VERSION 5.7 ;
  NOWIREEXTENSIONATPIN ON ;
  DIVIDERCHAR "/" ;
  BUSBITCHARS "[]" ;
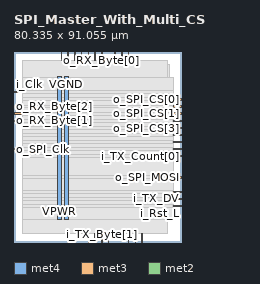
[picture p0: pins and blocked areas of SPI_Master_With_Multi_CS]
MACRO SPI_Master_With_Multi_CS
  CLASS BLOCK ;
  FOREIGN SPI_Master_With_Multi_CS ;
  ORIGIN 0.000 0.000 ;
  SIZE 80.335 BY 91.055 ;
  PIN VGND
    DIRECTION INOUT ;
    USE GROUND ;
    PORT
      LAYER met4 ;
        RECT 24.340 10.640 25.940 79.120 ;
    END
  END VGND
  PIN VPWR
    DIRECTION INOUT ;
    USE POWER ;
    PORT
      LAYER met4 ;
        RECT 21.040 10.640 22.640 79.120 ;
    END
  END VPWR
  PIN i_Clk
    DIRECTION INPUT ;
    USE SIGNAL ;
    ANTENNAGATEAREA 0.852000 ;
    PORT
      LAYER met3 ;
        RECT 0.000 71.440 4.000 72.040 ;
    END
  END i_Clk
  PIN i_Rst_L
    DIRECTION INPUT ;
    USE SIGNAL ;
    ANTENNAGATEAREA 0.196500 ;
    PORT
      LAYER met3 ;
        RECT 76.335 17.040 80.335 17.640 ;
    END
  END i_Rst_L
  PIN i_SPI_MISO
    DIRECTION INPUT ;
    USE SIGNAL ;
    ANTENNAGATEAREA 0.213000 ;
    PORT
      LAYER met2 ;
        RECT 29.070 87.055 29.350 91.055 ;
    END
  END i_SPI_MISO
  PIN i_Slave_Select[0]
    DIRECTION INPUT ;
    USE SIGNAL ;
    ANTENNAGATEAREA 0.196500 ;
    PORT
      LAYER met3 ;
        RECT 76.335 51.040 80.335 51.640 ;
    END
  END i_Slave_Select[0]
  PIN i_Slave_Select[1]
    DIRECTION INPUT ;
    USE SIGNAL ;
    ANTENNAGATEAREA 0.196500 ;
    PORT
      LAYER met3 ;
        RECT 76.335 54.440 80.335 55.040 ;
    END
  END i_Slave_Select[1]
  PIN i_TX_Byte[0]
    DIRECTION INPUT ;
    USE SIGNAL ;
    ANTENNAGATEAREA 0.196500 ;
    PORT
      LAYER met2 ;
        RECT 45.170 0.000 45.450 4.000 ;
    END
  END i_TX_Byte[0]
  PIN i_TX_Byte[1]
    DIRECTION INPUT ;
    USE SIGNAL ;
    ANTENNAGATEAREA 0.196500 ;
    PORT
      LAYER met2 ;
        RECT 41.950 0.000 42.230 4.000 ;
    END
  END i_TX_Byte[1]
  PIN i_TX_Byte[2]
    DIRECTION INPUT ;
    USE SIGNAL ;
    ANTENNAGATEAREA 0.196500 ;
    PORT
      LAYER met2 ;
        RECT 35.510 0.000 35.790 4.000 ;
    END
  END i_TX_Byte[2]
  PIN i_TX_Byte[3]
    DIRECTION INPUT ;
    USE SIGNAL ;
    ANTENNAGATEAREA 0.196500 ;
    PORT
      LAYER met2 ;
        RECT 38.730 0.000 39.010 4.000 ;
    END
  END i_TX_Byte[3]
  PIN i_TX_Byte[4]
    DIRECTION INPUT ;
    USE SIGNAL ;
    ANTENNAGATEAREA 0.196500 ;
    PORT
      LAYER met3 ;
        RECT 76.335 23.840 80.335 24.440 ;
    END
  END i_TX_Byte[4]
  PIN i_TX_Byte[5]
    DIRECTION INPUT ;
    USE SIGNAL ;
    ANTENNAGATEAREA 0.196500 ;
    PORT
      LAYER met2 ;
        RECT 61.270 0.000 61.550 4.000 ;
    END
  END i_TX_Byte[5]
  PIN i_TX_Byte[6]
    DIRECTION INPUT ;
    USE SIGNAL ;
    ANTENNAGATEAREA 0.196500 ;
    PORT
      LAYER met2 ;
        RECT 54.830 0.000 55.110 4.000 ;
    END
  END i_TX_Byte[6]
  PIN i_TX_Byte[7]
    DIRECTION INPUT ;
    USE SIGNAL ;
    ANTENNAGATEAREA 0.196500 ;
    PORT
      LAYER met2 ;
        RECT 58.050 0.000 58.330 4.000 ;
    END
  END i_TX_Byte[7]
  PIN i_TX_Count[0]
    DIRECTION INPUT ;
    USE SIGNAL ;
    ANTENNAGATEAREA 0.196500 ;
    PORT
      LAYER met3 ;
        RECT 76.335 40.840 80.335 41.440 ;
    END
  END i_TX_Count[0]
  PIN i_TX_Count[1]
    DIRECTION INPUT ;
    USE SIGNAL ;
    ANTENNAGATEAREA 0.196500 ;
    PORT
      LAYER met3 ;
        RECT 76.335 44.240 80.335 44.840 ;
    END
  END i_TX_Count[1]
  PIN i_TX_DV
    DIRECTION INPUT ;
    USE SIGNAL ;
    ANTENNAGATEAREA 0.196500 ;
    PORT
      LAYER met3 ;
        RECT 76.335 20.440 80.335 21.040 ;
    END
  END i_TX_DV
  PIN o_RX_Byte[0]
    DIRECTION OUTPUT ;
    USE SIGNAL ;
    ANTENNADIFFAREA 0.445500 ;
    PORT
      LAYER met2 ;
        RECT 41.950 87.055 42.230 91.055 ;
    END
  END o_RX_Byte[0]
  PIN o_RX_Byte[1]
    DIRECTION OUTPUT ;
    USE SIGNAL ;
    ANTENNADIFFAREA 0.445500 ;
    PORT
      LAYER met3 ;
        RECT 0.000 57.840 4.000 58.440 ;
    END
  END o_RX_Byte[1]
  PIN o_RX_Byte[2]
    DIRECTION OUTPUT ;
    USE SIGNAL ;
    ANTENNADIFFAREA 0.445500 ;
    PORT
      LAYER met3 ;
        RECT 0.000 61.240 4.000 61.840 ;
    END
  END o_RX_Byte[2]
  PIN o_RX_Byte[3]
    DIRECTION OUTPUT ;
    USE SIGNAL ;
    ANTENNADIFFAREA 0.445500 ;
    PORT
      LAYER met2 ;
        RECT 38.730 87.055 39.010 91.055 ;
    END
  END o_RX_Byte[3]
  PIN o_RX_Byte[4]
    DIRECTION OUTPUT ;
    USE SIGNAL ;
    ANTENNADIFFAREA 0.445500 ;
    PORT
      LAYER met2 ;
        RECT 32.290 87.055 32.570 91.055 ;
    END
  END o_RX_Byte[4]
  PIN o_RX_Byte[5]
    DIRECTION OUTPUT ;
    USE SIGNAL ;
    ANTENNADIFFAREA 0.445500 ;
    PORT
      LAYER met2 ;
        RECT 25.850 87.055 26.130 91.055 ;
    END
  END o_RX_Byte[5]
  PIN o_RX_Byte[6]
    DIRECTION OUTPUT ;
    USE SIGNAL ;
    ANTENNADIFFAREA 0.445500 ;
    PORT
      LAYER met2 ;
        RECT 22.630 87.055 22.910 91.055 ;
    END
  END o_RX_Byte[6]
  PIN o_RX_Byte[7]
    DIRECTION OUTPUT ;
    USE SIGNAL ;
    ANTENNADIFFAREA 0.445500 ;
    PORT
      LAYER met2 ;
        RECT 35.510 87.055 35.790 91.055 ;
    END
  END o_RX_Byte[7]
  PIN o_RX_Count[0]
    DIRECTION OUTPUT ;
    USE SIGNAL ;
    ANTENNADIFFAREA 0.445500 ;
    PORT
      LAYER met2 ;
        RECT 51.610 87.055 51.890 91.055 ;
    END
  END o_RX_Count[0]
  PIN o_RX_Count[1]
    DIRECTION OUTPUT ;
    USE SIGNAL ;
    ANTENNADIFFAREA 0.445500 ;
    PORT
      LAYER met2 ;
        RECT 54.830 87.055 55.110 91.055 ;
    END
  END o_RX_Count[1]
  PIN o_RX_DV
    DIRECTION OUTPUT ;
    USE SIGNAL ;
    ANTENNADIFFAREA 0.445500 ;
    PORT
      LAYER met2 ;
        RECT 48.390 87.055 48.670 91.055 ;
    END
  END o_RX_DV
  PIN o_SPI_CS[0]
    DIRECTION OUTPUT ;
    USE SIGNAL ;
    ANTENNADIFFAREA 0.445500 ;
    PORT
      LAYER met3 ;
        RECT 76.335 68.040 80.335 68.640 ;
    END
  END o_SPI_CS[0]
  PIN o_SPI_CS[1]
    DIRECTION OUTPUT ;
    USE SIGNAL ;
    ANTENNADIFFAREA 0.445500 ;
    PORT
      LAYER met3 ;
        RECT 76.335 64.640 80.335 65.240 ;
    END
  END o_SPI_CS[1]
  PIN o_SPI_CS[2]
    DIRECTION OUTPUT ;
    USE SIGNAL ;
    ANTENNADIFFAREA 0.445500 ;
    PORT
      LAYER met3 ;
        RECT 76.335 61.240 80.335 61.840 ;
    END
  END o_SPI_CS[2]
  PIN o_SPI_CS[3]
    DIRECTION OUTPUT ;
    USE SIGNAL ;
    ANTENNADIFFAREA 0.445500 ;
    PORT
      LAYER met3 ;
        RECT 76.335 57.840 80.335 58.440 ;
    END
  END o_SPI_CS[3]
  PIN o_SPI_Clk
    DIRECTION OUTPUT ;
    USE SIGNAL ;
    ANTENNADIFFAREA 0.445500 ;
    PORT
      LAYER met3 ;
        RECT 0.000 44.240 4.000 44.840 ;
    END
  END o_SPI_Clk
  PIN o_SPI_MOSI
    DIRECTION OUTPUT ;
    USE SIGNAL ;
    ANTENNADIFFAREA 0.445500 ;
    PORT
      LAYER met3 ;
        RECT 76.335 30.640 80.335 31.240 ;
    END
  END o_SPI_MOSI
  PIN o_TX_Ready
    DIRECTION OUTPUT ;
    USE SIGNAL ;
    ANTENNADIFFAREA 0.445500 ;
    PORT
      LAYER met3 ;
        RECT 76.335 47.640 80.335 48.240 ;
    END
  END o_TX_Ready
  OBS
      LAYER nwell ;
        RECT 5.330 10.795 74.710 79.070 ;
      LAYER li1 ;
        RECT 5.520 10.795 74.520 78.965 ;
      LAYER met1 ;
        RECT 4.210 10.640 74.520 84.960 ;
      LAYER met2 ;
        RECT 4.230 86.775 22.350 87.055 ;
        RECT 23.190 86.775 25.570 87.055 ;
        RECT 26.410 86.775 28.790 87.055 ;
        RECT 29.630 86.775 32.010 87.055 ;
        RECT 32.850 86.775 35.230 87.055 ;
        RECT 36.070 86.775 38.450 87.055 ;
        RECT 39.290 86.775 41.670 87.055 ;
        RECT 42.510 86.775 48.110 87.055 ;
        RECT 48.950 86.775 51.330 87.055 ;
        RECT 52.170 86.775 54.550 87.055 ;
        RECT 55.390 86.775 73.500 87.055 ;
        RECT 4.230 4.280 73.500 86.775 ;
        RECT 4.230 4.000 35.230 4.280 ;
        RECT 36.070 4.000 38.450 4.280 ;
        RECT 39.290 4.000 41.670 4.280 ;
        RECT 42.510 4.000 44.890 4.280 ;
        RECT 45.730 4.000 54.550 4.280 ;
        RECT 55.390 4.000 57.770 4.280 ;
        RECT 58.610 4.000 60.990 4.280 ;
        RECT 61.830 4.000 73.500 4.280 ;
      LAYER met3 ;
        RECT 3.990 72.440 76.335 79.045 ;
        RECT 4.400 71.040 76.335 72.440 ;
        RECT 3.990 69.040 76.335 71.040 ;
        RECT 3.990 67.640 75.935 69.040 ;
        RECT 3.990 65.640 76.335 67.640 ;
        RECT 3.990 64.240 75.935 65.640 ;
        RECT 3.990 62.240 76.335 64.240 ;
        RECT 4.400 60.840 75.935 62.240 ;
        RECT 3.990 58.840 76.335 60.840 ;
        RECT 4.400 57.440 75.935 58.840 ;
        RECT 3.990 55.440 76.335 57.440 ;
        RECT 3.990 54.040 75.935 55.440 ;
        RECT 3.990 52.040 76.335 54.040 ;
        RECT 3.990 50.640 75.935 52.040 ;
        RECT 3.990 48.640 76.335 50.640 ;
        RECT 3.990 47.240 75.935 48.640 ;
        RECT 3.990 45.240 76.335 47.240 ;
        RECT 4.400 43.840 75.935 45.240 ;
        RECT 3.990 41.840 76.335 43.840 ;
        RECT 3.990 40.440 75.935 41.840 ;
        RECT 3.990 31.640 76.335 40.440 ;
        RECT 3.990 30.240 75.935 31.640 ;
        RECT 3.990 24.840 76.335 30.240 ;
        RECT 3.990 23.440 75.935 24.840 ;
        RECT 3.990 21.440 76.335 23.440 ;
        RECT 3.990 20.040 75.935 21.440 ;
        RECT 3.990 18.040 76.335 20.040 ;
        RECT 3.990 16.640 75.935 18.040 ;
        RECT 3.990 10.715 76.335 16.640 ;
  END
END SPI_Master_With_Multi_CS
END LIBRARY

